VERSION 5.7 ;
  NOWIREEXTENSIONATPIN ON ;
  DIVIDERCHAR "/" ;
  BUSBITCHARS "[]" ;
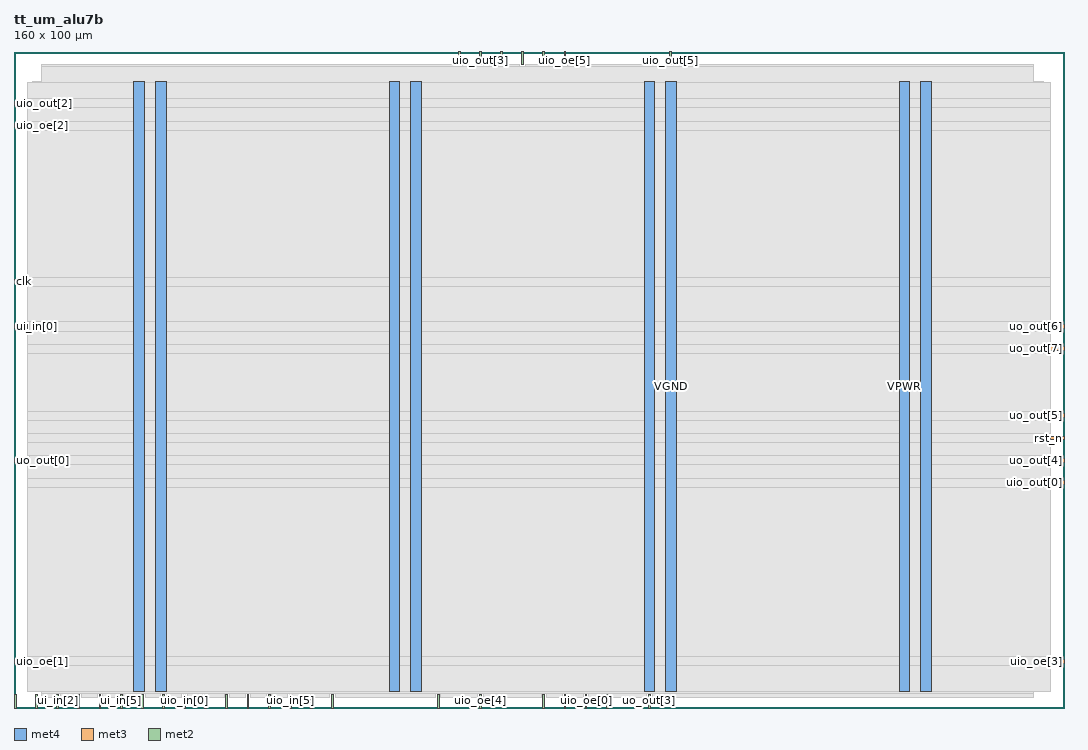
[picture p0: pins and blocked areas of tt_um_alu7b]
MACRO tt_um_alu7b
  CLASS BLOCK ;
  FOREIGN tt_um_alu7b ;
  ORIGIN 0.000 0.000 ;
  SIZE 160.000 BY 100.000 ;
  PIN VGND
    DIRECTION INOUT ;
    USE GROUND ;
    PORT
      LAYER met4 ;
        RECT 21.580 2.480 23.180 95.440 ;
    END
    PORT
      LAYER met4 ;
        RECT 60.450 2.480 62.050 95.440 ;
    END
    PORT
      LAYER met4 ;
        RECT 99.320 2.480 100.920 95.440 ;
    END
    PORT
      LAYER met4 ;
        RECT 138.190 2.480 139.790 95.440 ;
    END
  END VGND
  PIN VPWR
    DIRECTION INOUT ;
    USE POWER ;
    PORT
      LAYER met4 ;
        RECT 18.280 2.480 19.880 95.440 ;
    END
    PORT
      LAYER met4 ;
        RECT 57.150 2.480 58.750 95.440 ;
    END
    PORT
      LAYER met4 ;
        RECT 96.020 2.480 97.620 95.440 ;
    END
    PORT
      LAYER met4 ;
        RECT 134.890 2.480 136.490 95.440 ;
    END
  END VPWR
  PIN clk
    DIRECTION INPUT ;
    USE SIGNAL ;
    ANTENNAGATEAREA 0.852000 ;
    PORT
      LAYER met3 ;
        RECT 0.000 64.640 2.000 65.240 ;
    END
  END clk
  PIN ena
    DIRECTION INPUT ;
    USE SIGNAL ;
    PORT
      LAYER met2 ;
        RECT 0.090 0.000 0.370 2.000 ;
    END
  END ena
  PIN rst_n
    DIRECTION INPUT ;
    USE SIGNAL ;
    ANTENNAGATEAREA 0.196500 ;
    PORT
      LAYER met3 ;
        RECT 158.000 40.840 160.000 41.440 ;
    END
  END rst_n
  PIN ui_in[0]
    DIRECTION INPUT ;
    USE SIGNAL ;
    ANTENNAGATEAREA 0.196500 ;
    PORT
      LAYER met3 ;
        RECT 0.000 57.840 2.000 58.440 ;
    END
  END ui_in[0]
  PIN ui_in[1]
    DIRECTION INPUT ;
    USE SIGNAL ;
    PORT
      LAYER met2 ;
        RECT 3.310 0.000 3.590 2.000 ;
    END
  END ui_in[1]
  PIN ui_in[2]
    DIRECTION INPUT ;
    USE SIGNAL ;
    PORT
      LAYER met2 ;
        RECT 6.530 0.000 6.810 2.000 ;
    END
  END ui_in[2]
  PIN ui_in[3]
    DIRECTION INPUT ;
    USE SIGNAL ;
    PORT
      LAYER met2 ;
        RECT 9.750 0.000 10.030 2.000 ;
    END
  END ui_in[3]
  PIN ui_in[4]
    DIRECTION INPUT ;
    USE SIGNAL ;
    PORT
      LAYER met2 ;
        RECT 12.970 0.000 13.250 2.000 ;
    END
  END ui_in[4]
  PIN ui_in[5]
    DIRECTION INPUT ;
    USE SIGNAL ;
    PORT
      LAYER met2 ;
        RECT 16.190 0.000 16.470 2.000 ;
    END
  END ui_in[5]
  PIN ui_in[6]
    DIRECTION INPUT ;
    USE SIGNAL ;
    PORT
      LAYER met2 ;
        RECT 19.410 0.000 19.690 2.000 ;
    END
  END ui_in[6]
  PIN ui_in[7]
    DIRECTION INPUT ;
    USE SIGNAL ;
    PORT
      LAYER met2 ;
        RECT 22.630 0.000 22.910 2.000 ;
    END
  END ui_in[7]
  PIN uio_in[0]
    DIRECTION INPUT ;
    USE SIGNAL ;
    PORT
      LAYER met2 ;
        RECT 25.850 0.000 26.130 2.000 ;
    END
  END uio_in[0]
  PIN uio_in[1]
    DIRECTION INPUT ;
    USE SIGNAL ;
    PORT
      LAYER met2 ;
        RECT 29.070 0.000 29.350 2.000 ;
    END
  END uio_in[1]
  PIN uio_in[2]
    DIRECTION INPUT ;
    USE SIGNAL ;
    PORT
      LAYER met2 ;
        RECT 32.290 0.000 32.570 2.000 ;
    END
  END uio_in[2]
  PIN uio_in[3]
    DIRECTION INPUT ;
    USE SIGNAL ;
    PORT
      LAYER met2 ;
        RECT 35.510 0.000 35.790 2.000 ;
    END
  END uio_in[3]
  PIN uio_in[4]
    DIRECTION INPUT ;
    USE SIGNAL ;
    PORT
      LAYER met2 ;
        RECT 38.730 0.000 39.010 2.000 ;
    END
  END uio_in[4]
  PIN uio_in[5]
    DIRECTION INPUT ;
    USE SIGNAL ;
    PORT
      LAYER met2 ;
        RECT 41.950 0.000 42.230 2.000 ;
    END
  END uio_in[5]
  PIN uio_in[6]
    DIRECTION INPUT ;
    USE SIGNAL ;
    PORT
      LAYER met2 ;
        RECT 45.170 0.000 45.450 2.000 ;
    END
  END uio_in[6]
  PIN uio_in[7]
    DIRECTION INPUT ;
    USE SIGNAL ;
    PORT
      LAYER met2 ;
        RECT 48.390 0.000 48.670 2.000 ;
    END
  END uio_in[7]
  PIN uio_oe[0]
    DIRECTION OUTPUT ;
    USE SIGNAL ;
    PORT
      LAYER met2 ;
        RECT 87.030 0.000 87.310 2.000 ;
    END
  END uio_oe[0]
  PIN uio_oe[1]
    DIRECTION OUTPUT ;
    USE SIGNAL ;
    PORT
      LAYER met3 ;
        RECT 0.000 6.840 2.000 7.440 ;
    END
  END uio_oe[1]
  PIN uio_oe[2]
    DIRECTION OUTPUT ;
    USE SIGNAL ;
    PORT
      LAYER met3 ;
        RECT 0.000 88.440 2.000 89.040 ;
    END
  END uio_oe[2]
  PIN uio_oe[3]
    DIRECTION OUTPUT ;
    USE SIGNAL ;
    PORT
      LAYER met3 ;
        RECT 158.000 6.840 160.000 7.440 ;
    END
  END uio_oe[3]
  PIN uio_oe[4]
    DIRECTION OUTPUT ;
    USE SIGNAL ;
    PORT
      LAYER met2 ;
        RECT 70.930 0.000 71.210 2.000 ;
    END
  END uio_oe[4]
  PIN uio_oe[5]
    DIRECTION OUTPUT ;
    USE SIGNAL ;
    PORT
      LAYER met2 ;
        RECT 83.810 98.000 84.090 100.000 ;
    END
  END uio_oe[5]
  PIN uio_oe[6]
    DIRECTION OUTPUT ;
    USE SIGNAL ;
    PORT
      LAYER met2 ;
        RECT 74.150 98.000 74.430 100.000 ;
    END
  END uio_oe[6]
  PIN uio_oe[7]
    DIRECTION OUTPUT ;
    USE SIGNAL ;
    PORT
      LAYER met2 ;
        RECT 67.710 98.000 67.990 100.000 ;
    END
  END uio_oe[7]
  PIN uio_out[0]
    DIRECTION OUTPUT ;
    USE SIGNAL ;
    ANTENNADIFFAREA 0.445500 ;
    PORT
      LAYER met3 ;
        RECT 158.000 34.040 160.000 34.640 ;
    END
  END uio_out[0]
  PIN uio_out[1]
    DIRECTION OUTPUT ;
    USE SIGNAL ;
    PORT
      LAYER met2 ;
        RECT 77.370 98.000 77.650 100.000 ;
    END
  END uio_out[1]
  PIN uio_out[2]
    DIRECTION OUTPUT ;
    USE SIGNAL ;
    PORT
      LAYER met3 ;
        RECT 0.000 91.840 2.000 92.440 ;
    END
  END uio_out[2]
  PIN uio_out[3]
    DIRECTION OUTPUT ;
    USE SIGNAL ;
    PORT
      LAYER met2 ;
        RECT 70.930 98.000 71.210 100.000 ;
    END
  END uio_out[3]
  PIN uio_out[4]
    DIRECTION OUTPUT ;
    USE SIGNAL ;
    PORT
      LAYER met2 ;
        RECT 90.250 0.000 90.530 2.000 ;
    END
  END uio_out[4]
  PIN uio_out[5]
    DIRECTION OUTPUT ;
    USE SIGNAL ;
    PORT
      LAYER met2 ;
        RECT 99.910 98.000 100.190 100.000 ;
    END
  END uio_out[5]
  PIN uio_out[6]
    DIRECTION OUTPUT ;
    USE SIGNAL ;
    PORT
      LAYER met2 ;
        RECT 83.810 0.000 84.090 2.000 ;
    END
  END uio_out[6]
  PIN uio_out[7]
    DIRECTION OUTPUT ;
    USE SIGNAL ;
    PORT
      LAYER met2 ;
        RECT 80.590 98.000 80.870 100.000 ;
    END
  END uio_out[7]
  PIN uo_out[0]
    DIRECTION OUTPUT ;
    USE SIGNAL ;
    ANTENNAGATEAREA 0.247500 ;
    ANTENNADIFFAREA 0.891000 ;
    PORT
      LAYER met3 ;
        RECT 0.000 37.440 2.000 38.040 ;
    END
  END uo_out[0]
  PIN uo_out[1]
    DIRECTION OUTPUT ;
    USE SIGNAL ;
    ANTENNAGATEAREA 0.247500 ;
    ANTENNADIFFAREA 0.891000 ;
    PORT
      LAYER met2 ;
        RECT 64.490 0.000 64.770 2.000 ;
    END
  END uo_out[1]
  PIN uo_out[2]
    DIRECTION OUTPUT ;
    USE SIGNAL ;
    ANTENNAGATEAREA 0.126000 ;
    ANTENNADIFFAREA 0.891000 ;
    PORT
      LAYER met2 ;
        RECT 80.590 0.000 80.870 2.000 ;
    END
  END uo_out[2]
  PIN uo_out[3]
    DIRECTION OUTPUT ;
    USE SIGNAL ;
    ANTENNAGATEAREA 0.126000 ;
    ANTENNADIFFAREA 0.891000 ;
    PORT
      LAYER met2 ;
        RECT 96.690 0.000 96.970 2.000 ;
    END
  END uo_out[3]
  PIN uo_out[4]
    DIRECTION OUTPUT ;
    USE SIGNAL ;
    ANTENNAGATEAREA 0.126000 ;
    ANTENNADIFFAREA 0.891000 ;
    PORT
      LAYER met3 ;
        RECT 158.000 37.440 160.000 38.040 ;
    END
  END uo_out[4]
  PIN uo_out[5]
    DIRECTION OUTPUT ;
    USE SIGNAL ;
    ANTENNAGATEAREA 0.126000 ;
    ANTENNADIFFAREA 0.891000 ;
    PORT
      LAYER met3 ;
        RECT 158.000 44.240 160.000 44.840 ;
    END
  END uo_out[5]
  PIN uo_out[6]
    DIRECTION OUTPUT ;
    USE SIGNAL ;
    ANTENNAGATEAREA 0.247500 ;
    ANTENNADIFFAREA 0.891000 ;
    PORT
      LAYER met3 ;
        RECT 158.000 57.840 160.000 58.440 ;
    END
  END uo_out[6]
  PIN uo_out[7]
    DIRECTION OUTPUT ;
    USE SIGNAL ;
    ANTENNAGATEAREA 0.247500 ;
    ANTENNADIFFAREA 0.891000 ;
    PORT
      LAYER met3 ;
        RECT 158.000 54.440 160.000 55.040 ;
    END
  END uo_out[7]
  OBS
      LAYER nwell ;
        RECT 2.570 2.635 157.050 95.285 ;
      LAYER li1 ;
        RECT 2.760 2.635 156.860 95.285 ;
      LAYER met1 ;
        RECT 2.760 2.480 156.860 95.440 ;
      LAYER met2 ;
        RECT 4.230 97.720 67.430 98.000 ;
        RECT 68.270 97.720 70.650 98.000 ;
        RECT 71.490 97.720 73.870 98.000 ;
        RECT 74.710 97.720 77.090 98.000 ;
        RECT 77.930 97.720 80.310 98.000 ;
        RECT 81.150 97.720 83.530 98.000 ;
        RECT 84.370 97.720 99.630 98.000 ;
        RECT 100.470 97.720 155.390 98.000 ;
        RECT 4.230 2.280 155.390 97.720 ;
        RECT 4.230 1.630 6.250 2.280 ;
        RECT 7.090 1.630 9.470 2.280 ;
        RECT 10.310 1.630 12.690 2.280 ;
        RECT 13.530 1.630 15.910 2.280 ;
        RECT 16.750 1.630 19.130 2.280 ;
        RECT 19.970 1.630 22.350 2.280 ;
        RECT 23.190 1.630 25.570 2.280 ;
        RECT 26.410 1.630 28.790 2.280 ;
        RECT 29.630 1.630 32.010 2.280 ;
        RECT 32.850 1.630 35.230 2.280 ;
        RECT 36.070 1.630 38.450 2.280 ;
        RECT 39.290 1.630 41.670 2.280 ;
        RECT 42.510 1.630 44.890 2.280 ;
        RECT 45.730 1.630 48.110 2.280 ;
        RECT 48.950 1.630 64.210 2.280 ;
        RECT 65.050 1.630 70.650 2.280 ;
        RECT 71.490 1.630 80.310 2.280 ;
        RECT 81.150 1.630 83.530 2.280 ;
        RECT 84.370 1.630 86.750 2.280 ;
        RECT 87.590 1.630 89.970 2.280 ;
        RECT 90.810 1.630 96.410 2.280 ;
        RECT 97.250 1.630 155.390 2.280 ;
      LAYER met3 ;
        RECT 2.000 92.840 158.000 95.365 ;
        RECT 2.400 91.440 158.000 92.840 ;
        RECT 2.000 89.440 158.000 91.440 ;
        RECT 2.400 88.040 158.000 89.440 ;
        RECT 2.000 65.640 158.000 88.040 ;
        RECT 2.400 64.240 158.000 65.640 ;
        RECT 2.000 58.840 158.000 64.240 ;
        RECT 2.400 57.440 157.600 58.840 ;
        RECT 2.000 55.440 158.000 57.440 ;
        RECT 2.000 54.040 157.600 55.440 ;
        RECT 2.000 45.240 158.000 54.040 ;
        RECT 2.000 43.840 157.600 45.240 ;
        RECT 2.000 41.840 158.000 43.840 ;
        RECT 2.000 40.440 157.600 41.840 ;
        RECT 2.000 38.440 158.000 40.440 ;
        RECT 2.400 37.040 157.600 38.440 ;
        RECT 2.000 35.040 158.000 37.040 ;
        RECT 2.000 33.640 157.600 35.040 ;
        RECT 2.000 7.840 158.000 33.640 ;
        RECT 2.400 6.440 157.600 7.840 ;
        RECT 2.000 2.555 158.000 6.440 ;
  END
END tt_um_alu7b
END LIBRARY

